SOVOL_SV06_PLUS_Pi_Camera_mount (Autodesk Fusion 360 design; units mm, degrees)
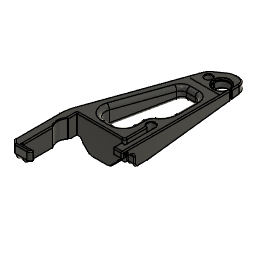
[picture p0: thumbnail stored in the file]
base_feature "Basiselement1"
remove_instance "Exemplar entfernen"
base_feature "Basiselement1"
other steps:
create_component "Komponente erstellen1"
create_component "Komponente erstellen1"
create_component "Komponente erstellen2"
